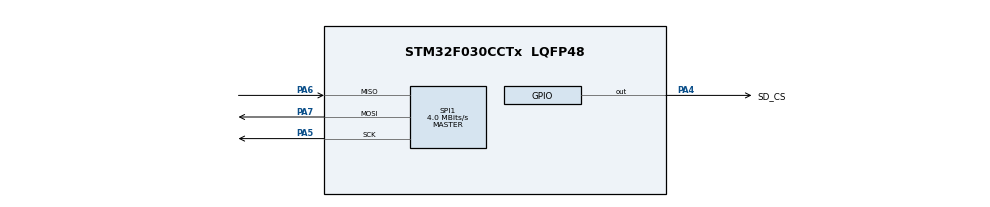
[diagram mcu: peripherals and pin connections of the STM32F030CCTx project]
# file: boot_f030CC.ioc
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FATFS._CODE_PAGE=437
FATFS._MAX_LFN=32
FATFS._USE_LFN=1
Mcu.Family=STM32F0
Mcu.Name=STM32F030CCTx
Mcu.Package=LQFP48
PA13.Mode=Serial_Wire
PA13.Signal=SYS_SWDIO
PA14.Mode=Serial_Wire
PA14.Signal=SYS_SWCLK
PA4.GPIO_Label=SD_CS
PA4.Signal=GPIO_Output
PA5.Mode=Full_Duplex_Master
PA5.Signal=SPI1_SCK
PA6.Mode=Full_Duplex_Master
PA6.Signal=SPI1_MISO
PA7.Mode=Full_Duplex_Master
PA7.Signal=SPI1_MOSI
ProjectManager.HeapSize=0x400
ProjectManager.StackSize=0x1000
ProjectManager.TargetToolchain=MDK-ARM V5
SPI1.CalculateBaudRate=4.0 MBits/s
SPI1.DataSize=SPI_DATASIZE_8BIT
SPI1.Direction=SPI_DIRECTION_2LINES
SPI1.Mode=SPI_MODE_MASTER
SPI1.VirtualType=VM_MASTER
VP_CRC_VS_CRC.Mode=CRC_Activate
VP_FATFS_VS_Generic.Mode=User_defined
board=custom

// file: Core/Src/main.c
/* USER CODE BEGIN Header */
/**
  ******************************************************************************
  * @file           : main.c
  * @brief          : Main program body
  ******************************************************************************
  * @attention
  *
  * <h2><center>&copy; Copyright (c) 2019 STMicroelectronics.
  * All rights reserved.</center></h2>
  *
  * This software component is licensed by ST under Ultimate Liberty license
  * SLA0044, the "License"; You may not use this file except in compliance with
  * the License. You may obtain a copy of the License at:
  *                             www.st.com/SLA0044
  *
  ******************************************************************************
  */
/* USER CODE END Header */

#include "main.h"
#include "fatfs.h"

/* USER CODE BEGIN Includes */
#include "fatfs_sd.h"
#include "string.h"
#include "flash_if.h"
#include "command.h"
#include "LCD.h"
#include "LCD_MENU.h"

/* USER CODE END Includes */

/* USER CODE BEGIN PD */
typedef  	void (*pFunction)(void);
pFunction 	JumpToApplication;
uint32_t 	JumpAddress;
uint32_t  	volatile  FlashProtection = 0;

/* USER CODE END PD */

CRC_HandleTypeDef hcrc;

SPI_HandleTypeDef hspi1;

/* USER CODE BEGIN PV */

uint8_t 	Download_to_flash(void);
void		Run_application(void);

/* USER CODE END PV */

void SystemClock_Config(void);
static void MX_GPIO_Init(void);
static void MX_CRC_Init(void);
static void MX_SPI1_Init(void);

/* USER CODE BEGIN 0 */
//FATFS fatfs;
//FIL fil;
//FRESULT fresult;
////char buff[20];
//UINT br, bw;

//const char DownloadFile[] = "APP.bin";

/* USER CODE END 0 */

int main(void)
{

  /* MCU Configuration--------------------------------------------------------*/

  /* Reset of all peripherals, Initializes the Flash interface and the Systick. */
  HAL_Init();

  /* Configure the system clock */
  SystemClock_Config();

  /* Initialize all configured peripherals */
  MX_GPIO_Init();
  MX_CRC_Init();
  MX_SPI1_Init();
  MX_FATFS_Init();

  /* Infinite loop */
  /* USER CODE BEGIN WHILE */

  startup();

  if(is_update_available()) {
	  //HAL_UART_Transmit(&huart1, (uint8_t*)"UPDATE AVAIABLE\r\n", strlen("UPDATE AVAIABLE\r\n"), 10);
	  LCD_Puts(0, 2, "UPDATE Available ...");
	  FLASH_If_Init();
	      /* Test if any sector of Flash memory where user application will be loaded is write protected */
	  FlashProtection = FLASH_If_GetWriteProtectionStatus();
	  if(Download_to_flash() == DOWNLOAD_OK) {
		  card_unlink();
		  LCD_Puts(0, 2, "    DOWNLOAD OK !   ");
		  //HAL_FLASH_OB_Launch();
	  }
	  else
			LCD_Puts(0, 2, "  DOWNLOAD FAILED ! ");

  }

  Run_application();

  while (1)
  {
    /* USER CODE END WHILE */

  }
}

void SystemClock_Config(void)
{
  RCC_OscInitTypeDef RCC_OscInitStruct = {0};
  RCC_ClkInitTypeDef RCC_ClkInitStruct = {0};

  /** Initializes the CPU, AHB and APB busses clocks
  */
  RCC_OscInitStruct.OscillatorType = RCC_OSCILLATORTYPE_HSI;
  RCC_OscInitStruct.HSIState = RCC_HSI_ON;
  RCC_OscInitStruct.HSICalibrationValue = RCC_HSICALIBRATION_DEFAULT;
  RCC_OscInitStruct.PLL.PLLState = RCC_PLL_NONE;
  if (HAL_RCC_OscConfig(&RCC_OscInitStruct) != HAL_OK)
  {
    Error_Handler();
  }
  /** Initializes the CPU, AHB and APB busses clocks
  */
  RCC_ClkInitStruct.ClockType = RCC_CLOCKTYPE_HCLK|RCC_CLOCKTYPE_SYSCLK
                              |RCC_CLOCKTYPE_PCLK1;
  RCC_ClkInitStruct.SYSCLKSource = RCC_SYSCLKSOURCE_HSI;
  RCC_ClkInitStruct.AHBCLKDivider = RCC_SYSCLK_DIV1;
  RCC_ClkInitStruct.APB1CLKDivider = RCC_HCLK_DIV1;

  if (HAL_RCC_ClockConfig(&RCC_ClkInitStruct, FLASH_LATENCY_0) != HAL_OK)
  {
    Error_Handler();
  }
}

static void MX_CRC_Init(void)
{

  hcrc.Instance = CRC;
  hcrc.Init.DefaultPolynomialUse = DEFAULT_POLYNOMIAL_ENABLE;
  hcrc.Init.DefaultInitValueUse = DEFAULT_INIT_VALUE_ENABLE;
  hcrc.Init.InputDataInversionMode = CRC_INPUTDATA_INVERSION_NONE;
  hcrc.Init.OutputDataInversionMode = CRC_OUTPUTDATA_INVERSION_DISABLE;
  hcrc.InputDataFormat = CRC_INPUTDATA_FORMAT_BYTES;
  if (HAL_CRC_Init(&hcrc) != HAL_OK)
  {
    Error_Handler();
  }

}

static void MX_SPI1_Init(void)
{

  /* SPI1 parameter configuration*/
  hspi1.Instance = SPI1;
  hspi1.Init.Mode = SPI_MODE_MASTER;
  hspi1.Init.Direction = SPI_DIRECTION_2LINES;
  hspi1.Init.DataSize = SPI_DATASIZE_8BIT;
  hspi1.Init.CLKPolarity = SPI_POLARITY_LOW;
  hspi1.Init.CLKPhase = SPI_PHASE_1EDGE;
  hspi1.Init.NSS = SPI_NSS_SOFT;
  hspi1.Init.BaudRatePrescaler = SPI_BAUDRATEPRESCALER_2;
  hspi1.Init.FirstBit = SPI_FIRSTBIT_MSB;
  hspi1.Init.TIMode = SPI_TIMODE_DISABLE;
  hspi1.Init.CRCCalculation = SPI_CRCCALCULATION_DISABLE;
  hspi1.Init.CRCPolynomial = 7;
  hspi1.Init.CRCLength = SPI_CRC_LENGTH_DATASIZE;
  hspi1.Init.NSSPMode = SPI_NSS_PULSE_ENABLE;
  if (HAL_SPI_Init(&hspi1) != HAL_OK)
  {
    Error_Handler();
  }

}

static void MX_GPIO_Init(void)
{
  GPIO_InitTypeDef GPIO_InitStruct = {0};

  /* GPIO Ports Clock Enable */
  __HAL_RCC_GPIOA_CLK_ENABLE();
  __HAL_RCC_GPIOB_CLK_ENABLE();

  /*Configure GPIO pin Output Level */
  HAL_GPIO_WritePin(SD_CS_GPIO_Port, SD_CS_Pin, GPIO_PIN_RESET);

  HAL_GPIO_WritePin(GPIOB, LCD_RS_Pin|LCD_D4_Pin|LCD_D5_Pin|LCD_D6_Pin|LCD_D7_Pin, GPIO_PIN_RESET);
  HAL_GPIO_WritePin(GPIOA, LCD_EN_Pin|LCD_RW_Pin, GPIO_PIN_RESET);

  /*Configure GPIO pins : SD_CS_Pin  LCD_EN_Pin */
  GPIO_InitStruct.Pin = SD_CS_Pin|LCD_EN_Pin|LCD_RW_Pin;
  GPIO_InitStruct.Mode = GPIO_MODE_OUTPUT_PP;
  GPIO_InitStruct.Pull = GPIO_NOPULL;
  GPIO_InitStruct.Speed = GPIO_SPEED_FREQ_LOW;
  HAL_GPIO_Init(GPIOA, &GPIO_InitStruct);

  /*Configure GPIO pins :  LCD_RS_Pin LCD_D4_Pin LCD_D5_Pin LCD_D6_Pin LCD_D7_Pin */
  GPIO_InitStruct.Pin = LCD_RS_Pin|LCD_D4_Pin|LCD_D5_Pin|LCD_D6_Pin|LCD_D7_Pin;
  GPIO_InitStruct.Mode = GPIO_MODE_OUTPUT_PP;
  GPIO_InitStruct.Pull = GPIO_NOPULL;
  GPIO_InitStruct.Speed = GPIO_SPEED_FREQ_LOW;
  HAL_GPIO_Init(GPIOB, &GPIO_InitStruct);

}

/* USER CODE BEGIN 4 */
//uint8_t is_update_available(void) {
////	fresult = f_mount(&fatfs, "", 1);
////	if(fresult != FR_OK)
////	  HAL_UART_Transmit(&huart1, (uint8_t*)"MOUNT ERR\r\n", strlen("MOUNT ERR\r\n"), 2000);
////	else
////	  HAL_UART_Transmit(&huart1, (uint8_t*)"Successfully MOUNT\r\n", strlen("Successfully MOUNT\r\n"), 2000);

////	fresult = f_open(&fil, "test.txt", FA_CREATE_ALWAYS | FA_WRITE);
////	f_puts("Save the world!!!", &fil);

////	/* Close file */
////	f_close(&fil);
////	f_open(&fil, "test.txt", FA_READ);
////	f_gets(buff, sizeof(buff), &fil);
////	HAL_UART_Transmit(&huart1, (uint8_t*)buff, sizeof(buff), 100);
//
//
//	if(f_mount(&fatfs, "", 1) == FR_OK)	{// Initialize file system
//		if (f_open(&fil, DownloadFile, FA_READ) == FR_OK) {	// Open application file
//			return TRUE;
//		}
//	}
//	return FALSE;
//}

uint8_t Download_to_flash(void) {
	return COMMAND_DOWNLOAD();
}

void Run_application(void) {
  /* Test if user code is programmed starting from address "APPLICATION_ADDRESS" */
  if (((*(__IO uint32_t*)APPLICATION_ADDRESS) & 0x2FFE0000 ) == 0x20000000)
  {
//	    __disable_irq();
//    memcpy((void*)0x20000000, (const void*)APPLICATION_ADDRESS, 0xc0 );
//
//	__HAL_SYSCFG_REMAPMEMORY_SRAM();
//    __enable_irq();
//	__DSB();

    /* Jump to user application */
    JumpAddress = *(__IO uint32_t*) (APPLICATION_ADDRESS + 4);
    JumpToApplication = (pFunction) JumpAddress;
    /* Initialize user application's Stack Pointer */

    __set_MSP(*(__IO uint32_t*) APPLICATION_ADDRESS);
//	  HAL_UART_Transmit(&huart1, (uint8_t*)"JUMP TO APP\r\n", strlen("JUMP TO APP\r\n"), 10);

    JumpToApplication();
  }
}

/* USER CODE END 4 */

void Error_Handler(void)
{
}

/************************ (C) COPYRIGHT STMicroelectronics *****END OF FILE****/
